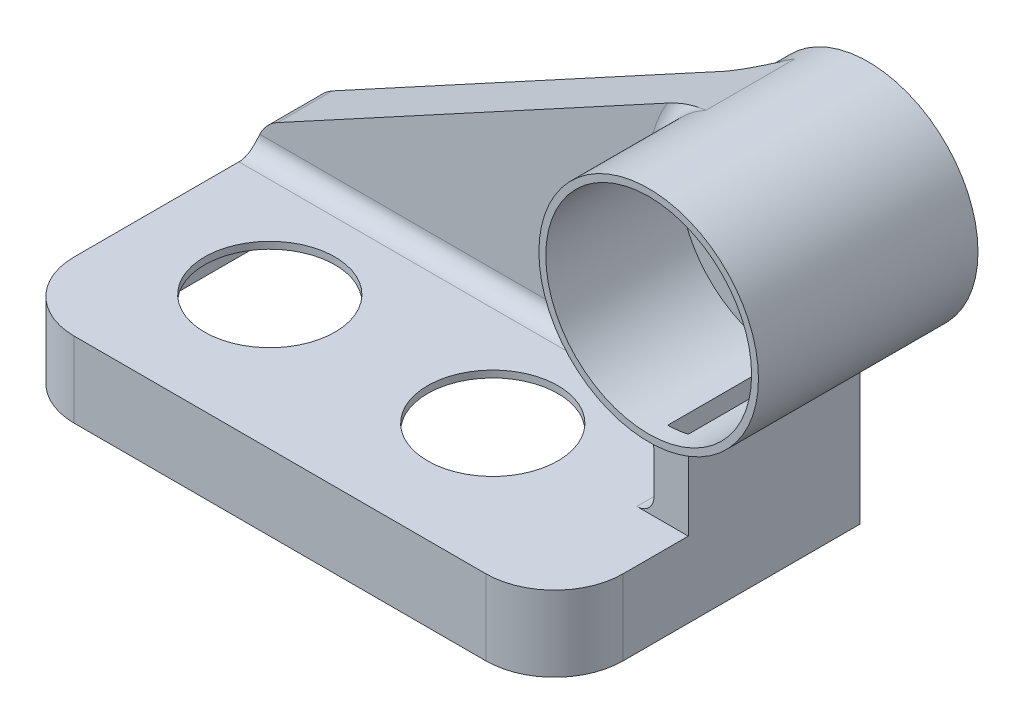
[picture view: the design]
ISO-10303-21;
HEADER;
FILE_DESCRIPTION(('STEP AP214'),'2;1');
FILE_NAME('part.step','',(''),(''),'','','');
FILE_SCHEMA(('AUTOMOTIVE_DESIGN { 1 0 10303 214 1 1 1 1 }'));
ENDSEC;
DATA;
#1=APPLICATION_CONTEXT('core data for automotive mechanical design processes');
#2=APPLICATION_PROTOCOL_DEFINITION('international standard','automotive_design',2000,#1);
#3=PRODUCT_CONTEXT('',#1,'mechanical');
#4=PRODUCT('Part','Part','',(#3));
#5=PRODUCT_RELATED_PRODUCT_CATEGORY('part','',(#4));
#6=PRODUCT_DEFINITION_FORMATION('','',#4);
#7=PRODUCT_DEFINITION_CONTEXT('part definition',#1,'design');
#8=PRODUCT_DEFINITION('design','',#6,#7);
#9=PRODUCT_DEFINITION_SHAPE('','',#8);
#10=(LENGTH_UNIT() NAMED_UNIT(*) SI_UNIT(.MILLI.,.METRE.));
#11=(NAMED_UNIT(*) PLANE_ANGLE_UNIT() SI_UNIT($,.RADIAN.));
#12=(NAMED_UNIT(*) SI_UNIT($,.STERADIAN.) SOLID_ANGLE_UNIT());
#13=UNCERTAINTY_MEASURE_WITH_UNIT(LENGTH_MEASURE(1.E-05),#10,'distance_accuracy_value','');
#14=(GEOMETRIC_REPRESENTATION_CONTEXT(3) GLOBAL_UNCERTAINTY_ASSIGNED_CONTEXT((#13)) GLOBAL_UNIT_ASSIGNED_CONTEXT((#10,
#11,#12)) REPRESENTATION_CONTEXT('',''));
#15=CARTESIAN_POINT('',(0.,0.,0.));
#16=DIRECTION('',(0.,0.,1.));
#17=DIRECTION('',(1.,0.,0.));
#18=AXIS2_PLACEMENT_3D('',#15,#16,#17);
#19=CARTESIAN_POINT('',(160.,22.,0.));
#20=DIRECTION('',(0.,1.,0.));
#21=DIRECTION('',(0.,0.,1.));
#22=AXIS2_PLACEMENT_3D('',#19,#20,#21);
#23=PLANE('',#22);
#24=CARTESIAN_POINT('',(38.,22.,-39.));
#25=DIRECTION('',(0.,1.,0.));
#26=DIRECTION('',(0.,0.,1.));
#27=AXIS2_PLACEMENT_3D('',#24,#25,#26);
#28=CIRCLE('',#27,19.);
#29=CARTESIAN_POINT('',(38.,22.,-20.));
#30=VERTEX_POINT('',#29);
#31=EDGE_CURVE('E988',#30,#30,#28,.T.);
#32=ORIENTED_EDGE('',*,*,#31,.F.);
#33=EDGE_LOOP('',(#32));
#34=FACE_BOUND('',#33,.T.);
#35=DIRECTION('',(0.,0.,1.));
#36=VECTOR('',#35,1.);
#37=CARTESIAN_POINT('',(145.,22.,0.));
#38=LINE('',#37,#36);
#39=CARTESIAN_POINT('',(145.,22.,-39.));
#40=VERTEX_POINT('',#39);
#41=CARTESIAN_POINT('',(145.,22.,-68.));
#42=VERTEX_POINT('',#41);
#43=EDGE_CURVE('E387',#40,#42,#38,.F.);
#44=ORIENTED_EDGE('',*,*,#43,.T.);
#45=DIRECTION('',(-1.,0.,0.));
#46=VECTOR('',#45,1.);
#47=CARTESIAN_POINT('',(160.,22.,-68.));
#48=LINE('',#47,#46);
#49=CARTESIAN_POINT('',(0.,22.,-68.));
#50=VERTEX_POINT('',#49);
#51=EDGE_CURVE('E484',#42,#50,#48,.T.);
#52=ORIENTED_EDGE('',*,*,#51,.T.);
#53=DIRECTION('',(0.,0.,-1.));
#54=VECTOR('',#53,1.);
#55=CARTESIAN_POINT('',(0.,22.,0.));
#56=LINE('',#55,#54);
#57=CARTESIAN_POINT('',(0.,22.,-20.));
#58=VERTEX_POINT('',#57);
#59=EDGE_CURVE('E403',#58,#50,#56,.T.);
#60=ORIENTED_EDGE('',*,*,#59,.F.);
#61=CARTESIAN_POINT('',(20.,22.,-20.));
#62=DIRECTION('',(0.,1.,0.));
#63=DIRECTION('',(0.,0.,1.));
#64=AXIS2_PLACEMENT_3D('',#61,#62,#63);
#65=CIRCLE('',#64,20.);
#66=CARTESIAN_POINT('',(20.,22.,0.));
#67=VERTEX_POINT('',#66);
#68=EDGE_CURVE('E437',#58,#67,#65,.T.);
#69=ORIENTED_EDGE('',*,*,#68,.T.);
#70=DIRECTION('',(1.,0.,0.));
#71=VECTOR('',#70,1.);
#72=CARTESIAN_POINT('',(0.,22.,0.));
#73=LINE('',#72,#71);
#74=CARTESIAN_POINT('',(140.,22.,0.));
#75=VERTEX_POINT('',#74);
#76=EDGE_CURVE('E372',#67,#75,#73,.T.);
#77=ORIENTED_EDGE('',*,*,#76,.T.);
#78=CARTESIAN_POINT('',(140.,22.,-20.));
#79=DIRECTION('',(0.,1.,0.));
#80=DIRECTION('',(0.,0.,1.));
#81=AXIS2_PLACEMENT_3D('',#78,#79,#80);
#82=CIRCLE('',#81,20.);
#83=CARTESIAN_POINT('',(160.,22.,-20.));
#84=VERTEX_POINT('',#83);
#85=EDGE_CURVE('E434',#75,#84,#82,.T.);
#86=ORIENTED_EDGE('',*,*,#85,.T.);
#87=DIRECTION('',(0.,0.,1.));
#88=VECTOR('',#87,1.);
#89=CARTESIAN_POINT('',(160.,22.,-89.));
#90=LINE('',#89,#88);
#91=CARTESIAN_POINT('',(160.,22.,-39.));
#92=VERTEX_POINT('',#91);
#93=EDGE_CURVE('E375',#92,#84,#90,.T.);
#94=ORIENTED_EDGE('',*,*,#93,.F.);
#95=DIRECTION('',(-1.,0.,0.));
#96=VECTOR('',#95,1.);
#97=CARTESIAN_POINT('',(160.,22.,-39.));
#98=LINE('',#97,#96);
#99=EDGE_CURVE('E337',#92,#40,#98,.T.);
#100=ORIENTED_EDGE('',*,*,#99,.T.);
#101=EDGE_LOOP('',(#44,#52,#60,#69,#77,#86,#94,#100));
#102=FACE_BOUND('',#101,.T.);
#103=CARTESIAN_POINT('',(103.,22.,-39.));
#104=DIRECTION('',(0.,1.,0.));
#105=DIRECTION('',(0.,0.,1.));
#106=AXIS2_PLACEMENT_3D('',#103,#104,#105);
#107=CIRCLE('',#106,19.);
#108=CARTESIAN_POINT('',(103.,22.,-20.));
#109=VERTEX_POINT('',#108);
#110=EDGE_CURVE('E499',#109,#109,#107,.T.);
#111=ORIENTED_EDGE('',*,*,#110,.F.);
#112=EDGE_LOOP('',(#111));
#113=FACE_BOUND('',#112,.T.);
#114=ADVANCED_FACE('F34',(#34,#102,#113),#23,.T.);
#115=CARTESIAN_POINT('',(160.,20.,0.));
#116=DIRECTION('',(0.,1.,0.));
#117=DIRECTION('',(0.,0.,1.));
#118=AXIS2_PLACEMENT_3D('',#115,#116,#117);
#119=PLANE('',#118);
#120=CARTESIAN_POINT('',(38.,20.,-39.));
#121=DIRECTION('',(0.,1.,0.));
#122=DIRECTION('',(0.,0.,1.));
#123=AXIS2_PLACEMENT_3D('',#120,#121,#122);
#124=CIRCLE('',#123,19.);
#125=CARTESIAN_POINT('',(38.,20.,-20.));
#126=VERTEX_POINT('',#125);
#127=EDGE_CURVE('E304',#126,#126,#124,.T.);
#128=ORIENTED_EDGE('',*,*,#127,.T.);
#129=EDGE_LOOP('',(#128));
#130=FACE_BOUND('',#129,.T.);
#131=DIRECTION('',(-1.,0.,0.));
#132=VECTOR('',#131,1.);
#133=CARTESIAN_POINT('',(160.,20.,-41.));
#134=LINE('',#133,#132);
#135=CARTESIAN_POINT('',(158.,20.,-41.));
#136=VERTEX_POINT('',#135);
#137=CARTESIAN_POINT('',(152.,20.,-41.));
#138=VERTEX_POINT('',#137);
#139=EDGE_CURVE('E227',#136,#138,#134,.T.);
#140=ORIENTED_EDGE('',*,*,#139,.F.);
#141=DIRECTION('',(0.,0.,1.));
#142=VECTOR('',#141,1.);
#143=CARTESIAN_POINT('',(158.,20.,-89.));
#144=LINE('',#143,#142);
#145=CARTESIAN_POINT('',(158.,20.,-20.));
#146=VERTEX_POINT('',#145);
#147=EDGE_CURVE('E269',#136,#146,#144,.T.);
#148=ORIENTED_EDGE('',*,*,#147,.T.);
#149=CARTESIAN_POINT('',(140.,20.,-20.));
#150=DIRECTION('',(0.,1.,0.));
#151=DIRECTION('',(0.,0.,1.));
#152=AXIS2_PLACEMENT_3D('',#149,#150,#151);
#153=CIRCLE('',#152,18.);
#154=CARTESIAN_POINT('',(140.,20.,-2.));
#155=VERTEX_POINT('',#154);
#156=EDGE_CURVE('E266',#155,#146,#153,.T.);
#157=ORIENTED_EDGE('',*,*,#156,.F.);
#158=DIRECTION('',(1.,0.,0.));
#159=VECTOR('',#158,1.);
#160=CARTESIAN_POINT('',(0.,20.,-2.));
#161=LINE('',#160,#159);
#162=CARTESIAN_POINT('',(20.,20.,-2.));
#163=VERTEX_POINT('',#162);
#164=EDGE_CURVE('E262',#163,#155,#161,.T.);
#165=ORIENTED_EDGE('',*,*,#164,.F.);
#166=CARTESIAN_POINT('',(20.,20.,-20.));
#167=DIRECTION('',(0.,1.,0.));
#168=DIRECTION('',(0.,0.,1.));
#169=AXIS2_PLACEMENT_3D('',#166,#167,#168);
#170=CIRCLE('',#169,18.);
#171=CARTESIAN_POINT('',(2.,20.,-20.));
#172=VERTEX_POINT('',#171);
#173=EDGE_CURVE('E263',#172,#163,#170,.T.);
#174=ORIENTED_EDGE('',*,*,#173,.F.);
#175=DIRECTION('',(0.,0.,-1.));
#176=VECTOR('',#175,1.);
#177=CARTESIAN_POINT('',(2.,20.,0.));
#178=LINE('',#177,#176);
#179=CARTESIAN_POINT('',(2.,20.,-75.));
#180=VERTEX_POINT('',#179);
#181=EDGE_CURVE('E259',#172,#180,#178,.T.);
#182=ORIENTED_EDGE('',*,*,#181,.T.);
#183=DIRECTION('',(-1.,0.,0.));
#184=VECTOR('',#183,1.);
#185=CARTESIAN_POINT('',(160.,20.,-75.));
#186=LINE('',#185,#184);
#187=CARTESIAN_POINT('',(152.,20.,-75.));
#188=VERTEX_POINT('',#187);
#189=EDGE_CURVE('E250',#188,#180,#186,.T.);
#190=ORIENTED_EDGE('',*,*,#189,.F.);
#191=DIRECTION('',(0.,0.,1.));
#192=VECTOR('',#191,1.);
#193=CARTESIAN_POINT('',(152.,20.,-73.));
#194=LINE('',#193,#192);
#195=EDGE_CURVE('E241',#188,#138,#194,.T.);
#196=ORIENTED_EDGE('',*,*,#195,.T.);
#197=EDGE_LOOP('',(#140,#148,#157,#165,#174,#182,#190,#196));
#198=FACE_BOUND('',#197,.T.);
#199=CARTESIAN_POINT('',(103.,20.,-39.));
#200=DIRECTION('',(0.,1.,0.));
#201=DIRECTION('',(0.,0.,1.));
#202=AXIS2_PLACEMENT_3D('',#199,#200,#201);
#203=CIRCLE('',#202,19.);
#204=CARTESIAN_POINT('',(103.,20.,-20.));
#205=VERTEX_POINT('',#204);
#206=EDGE_CURVE('E501',#205,#205,#203,.T.);
#207=ORIENTED_EDGE('',*,*,#206,.T.);
#208=EDGE_LOOP('',(#207));
#209=FACE_BOUND('',#208,.T.);
#210=ADVANCED_FACE('F247',(#130,#198,#209),#119,.F.);
#211=CARTESIAN_POINT('',(151.451853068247,75.,-73.));
#212=DIRECTION('',(0.,0.,-1.));
#213=DIRECTION('',(-1.,0.,0.));
#214=AXIS2_PLACEMENT_3D('',#211,#212,#213);
#215=PLANE('',#214);
#216=DIRECTION('',(0.,-1.,0.));
#217=VECTOR('',#216,1.);
#218=CARTESIAN_POINT('',(145.,38.5668613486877,-73.));
#219=LINE('',#218,#217);
#220=CARTESIAN_POINT('',(145.,27.,-73.));
#221=VERTEX_POINT('',#220);
#222=CARTESIAN_POINT('',(145.,38.5668613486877,-73.));
#223=VERTEX_POINT('',#222);
#224=EDGE_CURVE('E702',#221,#223,#219,.F.);
#225=ORIENTED_EDGE('',*,*,#224,.T.);
#226=CARTESIAN_POINT('',(151.451853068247,75.,-73.));
#227=DIRECTION('',(0.,0.,-1.));
#228=DIRECTION('',(-1.,0.,0.));
#229=AXIS2_PLACEMENT_3D('',#226,#227,#228);
#230=CIRCLE('',#229,37.);
#231=CARTESIAN_POINT('',(119.854697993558,94.2514880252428,-73.));
#232=VERTEX_POINT('',#231);
#233=EDGE_CURVE('E695',#223,#232,#230,.T.);
#234=ORIENTED_EDGE('',*,*,#233,.T.);
#235=DIRECTION('',(0.878698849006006,0.477376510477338,0.));
#236=VECTOR('',#235,1.);
#237=CARTESIAN_POINT('',(6.27148187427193,32.5443861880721,-73.));
#238=LINE('',#237,#236);
#239=CARTESIAN_POINT('',(6.27148187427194,32.5443861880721,-73.));
#240=VERTEX_POINT('',#239);
#241=EDGE_CURVE('E354',#240,#232,#238,.T.);
#242=ORIENTED_EDGE('',*,*,#241,.F.);
#243=CARTESIAN_POINT('',(12.,22.,-73.));
#244=DIRECTION('',(0.,0.,-1.));
#245=DIRECTION('',(-1.,0.,0.));
#246=AXIS2_PLACEMENT_3D('',#243,#244,#245);
#247=CIRCLE('',#246,12.);
#248=CARTESIAN_POINT('',(1.09128788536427,27.,-73.));
#249=VERTEX_POINT('',#248);
#250=EDGE_CURVE('E357',#249,#240,#247,.T.);
#251=ORIENTED_EDGE('',*,*,#250,.F.);
#252=DIRECTION('',(-1.,0.,0.));
#253=VECTOR('',#252,1.);
#254=CARTESIAN_POINT('',(151.451853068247,27.,-73.));
#255=LINE('',#254,#253);
#256=EDGE_CURVE('E397',#249,#221,#255,.F.);
#257=ORIENTED_EDGE('',*,*,#256,.T.);
#258=EDGE_LOOP('',(#225,#234,#242,#251,#257));
#259=FACE_BOUND('',#258,.T.);
#260=ADVANCED_FACE('F531',(#259),#215,.F.);
#261=CARTESIAN_POINT('',(160.,22.,-89.));
#262=DIRECTION('',(1.,0.,0.));
#263=DIRECTION('',(0.,0.,-1.));
#264=AXIS2_PLACEMENT_3D('',#261,#262,#263);
#265=PLANE('',#264);
#266=DIRECTION('',(0.,-1.,0.));
#267=VECTOR('',#266,1.);
#268=CARTESIAN_POINT('',(160.,107.001,-39.));
#269=LINE('',#268,#267);
#270=CARTESIAN_POINT('',(160.,44.1628603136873,-39.));
#271=VERTEX_POINT('',#270);
#272=EDGE_CURVE('E322',#271,#92,#269,.T.);
#273=ORIENTED_EDGE('',*,*,#272,.T.);
#274=ORIENTED_EDGE('',*,*,#93,.T.);
#275=DIRECTION('',(0.,-1.,0.));
#276=VECTOR('',#275,1.);
#277=CARTESIAN_POINT('',(160.,0.,-20.));
#278=LINE('',#277,#276);
#279=CARTESIAN_POINT('',(160.,0.,-20.));
#280=VERTEX_POINT('',#279);
#281=EDGE_CURVE('E385',#84,#280,#278,.T.);
#282=ORIENTED_EDGE('',*,*,#281,.T.);
#283=DIRECTION('',(0.,0.,1.));
#284=VECTOR('',#283,1.);
#285=CARTESIAN_POINT('',(160.,0.,-89.));
#286=LINE('',#285,#284);
#287=CARTESIAN_POINT('',(160.,0.,-89.));
#288=VERTEX_POINT('',#287);
#289=EDGE_CURVE('E369',#288,#280,#286,.T.);
#290=ORIENTED_EDGE('',*,*,#289,.F.);
#291=DIRECTION('',(0.,-1.,0.));
#292=VECTOR('',#291,1.);
#293=CARTESIAN_POINT('',(160.,22.,-89.));
#294=LINE('',#293,#292);
#295=CARTESIAN_POINT('',(160.,39.0009835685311,-89.));
#296=VERTEX_POINT('',#295);
#297=EDGE_CURVE('E418',#296,#288,#294,.T.);
#298=ORIENTED_EDGE('',*,*,#297,.F.);
#299=CARTESIAN_POINT('',(160.,39.0009835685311,-89.));
#300=CARTESIAN_POINT('',(160.,39.1493082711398,-88.9999869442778));
#301=CARTESIAN_POINT('',(160.,39.2976299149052,-89.0062472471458));
#302=CARTESIAN_POINT('',(160.,39.5932205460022,-89.031194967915));
#303=CARTESIAN_POINT('',(160.,39.7404895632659,-89.0498820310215));
#304=CARTESIAN_POINT('',(160.,40.0329217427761,-89.0995610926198));
#305=CARTESIAN_POINT('',(160.,40.1780851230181,-89.1305518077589));
#306=CARTESIAN_POINT('',(160.,40.4652910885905,-89.2046278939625));
#307=CARTESIAN_POINT('',(160.,40.6073337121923,-89.2477131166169));
#308=CARTESIAN_POINT('',(160.,40.8873409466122,-89.3457233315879));
#309=CARTESIAN_POINT('',(160.,41.0253038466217,-89.4006532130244));
#310=CARTESIAN_POINT('',(160.,41.2961367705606,-89.5220164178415));
#311=CARTESIAN_POINT('',(160.,41.4290048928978,-89.5884539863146));
#312=CARTESIAN_POINT('',(160.,41.6885226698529,-89.7323508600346));
#313=CARTESIAN_POINT('',(160.,41.8151762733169,-89.8098030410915));
#314=CARTESIAN_POINT('',(160.,42.0614332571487,-89.9752942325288));
#315=CARTESIAN_POINT('',(160.,42.1810342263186,-90.0633368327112));
#316=CARTESIAN_POINT('',(160.,42.411071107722,-90.2485064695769));
#317=CARTESIAN_POINT('',(160.,42.5215849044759,-90.3455367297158));
#318=CARTESIAN_POINT('',(160.,42.7338431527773,-90.5487553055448));
#319=CARTESIAN_POINT('',(160.,42.835587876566,-90.6549433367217));
#320=CARTESIAN_POINT('',(160.,43.0295005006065,-90.8758002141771));
#321=CARTESIAN_POINT('',(160.,43.1216650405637,-90.9904720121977));
#322=CARTESIAN_POINT('',(160.,43.2955459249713,-91.2274149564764));
#323=CARTESIAN_POINT('',(160.,43.3772664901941,-91.3496830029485));
#324=CARTESIAN_POINT('',(160.,43.5273765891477,-91.5973559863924));
#325=CARTESIAN_POINT('',(160.,43.596081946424,-91.7225695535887));
#326=CARTESIAN_POINT('',(160.,43.7223565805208,-91.9784296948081));
#327=CARTESIAN_POINT('',(160.,43.7799305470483,-92.1090739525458));
#328=CARTESIAN_POINT('',(160.,43.8834172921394,-92.37479813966));
#329=CARTESIAN_POINT('',(160.,43.9293383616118,-92.5098748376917));
#330=CARTESIAN_POINT('',(160.,44.0091328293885,-92.783488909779));
#331=CARTESIAN_POINT('',(160.,44.0430103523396,-92.9220250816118));
#332=CARTESIAN_POINT('',(160.,44.1013218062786,-93.2162653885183));
#333=CARTESIAN_POINT('',(160.,44.1243876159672,-93.372242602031));
#334=CARTESIAN_POINT('',(160.,44.155163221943,-93.6854814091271));
#335=CARTESIAN_POINT('',(160.,44.1628945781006,-93.8427408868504));
#336=CARTESIAN_POINT('',(160.,44.1628603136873,-94.));
#337=B_SPLINE_CURVE_WITH_KNOTS('',3,(#299,#300,#301,#302,#303,#304,#305,#306,#307,#308,#309,
#310,#311,#312,#313,#314,#315,#316,#317,#318,#319,#320,#321,#322,#323,#324,#325,#326,#327,#328,
#329,#330,#331,#332,#333,#334,#335,#336),.UNSPECIFIED.,.F.,.F.,(4,2,2,2,2,2,2,2,2,2,2,2,2,2,2,2,
2,2,4),(0.,0.444837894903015,0.889663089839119,1.33444189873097,1.77921525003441,
2.2241725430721,2.66929432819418,3.11412950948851,3.5591159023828,3.99977052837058,
4.44041146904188,4.88120644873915,5.32182272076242,5.74976598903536,6.17752856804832,
6.60498593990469,7.03229677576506,7.50455378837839,7.9761463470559),.UNSPECIFIED.);
#338=CARTESIAN_POINT('',(160.,44.1628603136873,-94.));
#339=VERTEX_POINT('',#338);
#340=EDGE_CURVE('E59',#296,#339,#337,.T.);
#341=ORIENTED_EDGE('',*,*,#340,.T.);
#342=DIRECTION('',(0.,0.,-1.));
#343=VECTOR('',#342,1.);
#344=CARTESIAN_POINT('',(160.,44.1628603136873,-73.));
#345=LINE('',#344,#343);
#346=EDGE_CURVE('E367',#271,#339,#345,.T.);
#347=ORIENTED_EDGE('',*,*,#346,.F.);
#348=EDGE_LOOP('',(#273,#274,#282,#290,#298,#341,#347));
#349=FACE_BOUND('',#348,.T.);
#350=ADVANCED_FACE('F443',(#349),#265,.T.);
#351=CARTESIAN_POINT('',(160.,22.,-89.));
#352=DIRECTION('',(0.,0.,1.));
#353=DIRECTION('',(1.,0.,0.));
#354=AXIS2_PLACEMENT_3D('',#351,#352,#353);
#355=PLANE('',#354);
#356=DIRECTION('',(0.878698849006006,0.477376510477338,0.));
#357=VECTOR('',#356,1.);
#358=CARTESIAN_POINT('',(6.27148187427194,32.5443861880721,-89.));
#359=LINE('',#358,#357);
#360=CARTESIAN_POINT('',(6.27148187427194,32.5443861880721,-89.));
#361=VERTEX_POINT('',#360);
#362=CARTESIAN_POINT('',(119.854697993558,94.2514880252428,-89.));
#363=VERTEX_POINT('',#362);
#364=EDGE_CURVE('E351',#361,#363,#359,.T.);
#365=ORIENTED_EDGE('',*,*,#364,.T.);
#366=CARTESIAN_POINT('',(151.451853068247,75.,-89.));
#367=DIRECTION('',(0.,0.,1.));
#368=DIRECTION('',(1.,0.,0.));
#369=AXIS2_PLACEMENT_3D('',#366,#367,#368);
#370=CIRCLE('',#369,37.);
#371=EDGE_CURVE('E492',#363,#296,#370,.T.);
#372=ORIENTED_EDGE('',*,*,#371,.T.);
#373=ORIENTED_EDGE('',*,*,#297,.T.);
#374=DIRECTION('',(-1.,0.,0.));
#375=VECTOR('',#374,1.);
#376=CARTESIAN_POINT('',(160.,0.,-89.));
#377=LINE('',#376,#375);
#378=CARTESIAN_POINT('',(0.,0.,-89.));
#379=VERTEX_POINT('',#378);
#380=EDGE_CURVE('E378',#288,#379,#377,.T.);
#381=ORIENTED_EDGE('',*,*,#380,.T.);
#382=DIRECTION('',(0.,-1.,0.));
#383=VECTOR('',#382,1.);
#384=CARTESIAN_POINT('',(0.,22.,-89.));
#385=LINE('',#384,#383);
#386=CARTESIAN_POINT('',(0.,22.,-89.));
#387=VERTEX_POINT('',#386);
#388=EDGE_CURVE('E411',#387,#379,#385,.T.);
#389=ORIENTED_EDGE('',*,*,#388,.F.);
#390=CARTESIAN_POINT('',(12.,22.,-89.));
#391=DIRECTION('',(0.,0.,-1.));
#392=DIRECTION('',(-1.,0.,0.));
#393=AXIS2_PLACEMENT_3D('',#390,#391,#392);
#394=CIRCLE('',#393,12.);
#395=EDGE_CURVE('E358',#387,#361,#394,.T.);
#396=ORIENTED_EDGE('',*,*,#395,.T.);
#397=EDGE_LOOP('',(#365,#372,#373,#381,#389,#396));
#398=FACE_BOUND('',#397,.T.);
#399=ADVANCED_FACE('F416',(#398),#355,.F.);
#400=CARTESIAN_POINT('',(0.,22.,0.));
#401=DIRECTION('',(-1.,0.,0.));
#402=DIRECTION('',(0.,0.,1.));
#403=AXIS2_PLACEMENT_3D('',#400,#401,#402);
#404=PLANE('',#403);
#405=DIRECTION('',(0.,0.,-1.));
#406=VECTOR('',#405,1.);
#407=CARTESIAN_POINT('',(0.,0.,0.));
#408=LINE('',#407,#406);
#409=CARTESIAN_POINT('',(0.,0.,-20.));
#410=VERTEX_POINT('',#409);
#411=EDGE_CURVE('E453',#410,#379,#408,.T.);
#412=ORIENTED_EDGE('',*,*,#411,.F.);
#413=DIRECTION('',(0.,-1.,0.));
#414=VECTOR('',#413,1.);
#415=CARTESIAN_POINT('',(0.,22.,-20.));
#416=LINE('',#415,#414);
#417=EDGE_CURVE('E432',#410,#58,#416,.F.);
#418=ORIENTED_EDGE('',*,*,#417,.T.);
#419=ORIENTED_EDGE('',*,*,#59,.T.);
#420=DIRECTION('',(0.,0.,-1.));
#421=VECTOR('',#420,1.);
#422=CARTESIAN_POINT('',(0.,22.,-73.));
#423=LINE('',#422,#421);
#424=EDGE_CURVE('E51',#50,#387,#423,.T.);
#425=ORIENTED_EDGE('',*,*,#424,.T.);
#426=ORIENTED_EDGE('',*,*,#388,.T.);
#427=EDGE_LOOP('',(#412,#418,#419,#425,#426));
#428=FACE_BOUND('',#427,.T.);
#429=ADVANCED_FACE('F410',(#428),#404,.T.);
#430=CARTESIAN_POINT('',(0.,22.,0.));
#431=DIRECTION('',(0.,0.,-1.));
#432=DIRECTION('',(-1.,0.,0.));
#433=AXIS2_PLACEMENT_3D('',#430,#431,#432);
#434=PLANE('',#433);
#435=ORIENTED_EDGE('',*,*,#76,.F.);
#436=DIRECTION('',(0.,-1.,0.));
#437=VECTOR('',#436,1.);
#438=CARTESIAN_POINT('',(20.,0.,0.));
#439=LINE('',#438,#437);
#440=CARTESIAN_POINT('',(20.,0.,0.));
#441=VERTEX_POINT('',#440);
#442=EDGE_CURVE('E425',#67,#441,#439,.T.);
#443=ORIENTED_EDGE('',*,*,#442,.T.);
#444=DIRECTION('',(1.,0.,0.));
#445=VECTOR('',#444,1.);
#446=CARTESIAN_POINT('',(0.,0.,0.));
#447=LINE('',#446,#445);
#448=CARTESIAN_POINT('',(140.,0.,0.));
#449=VERTEX_POINT('',#448);
#450=EDGE_CURVE('E451',#441,#449,#447,.T.);
#451=ORIENTED_EDGE('',*,*,#450,.T.);
#452=DIRECTION('',(0.,-1.,0.));
#453=VECTOR('',#452,1.);
#454=CARTESIAN_POINT('',(140.,22.,0.));
#455=LINE('',#454,#453);
#456=EDGE_CURVE('E420',#449,#75,#455,.F.);
#457=ORIENTED_EDGE('',*,*,#456,.T.);
#458=EDGE_LOOP('',(#435,#443,#451,#457));
#459=FACE_BOUND('',#458,.T.);
#460=ADVANCED_FACE('F467',(#459),#434,.F.);
#461=CARTESIAN_POINT('',(160.,0.,0.));
#462=DIRECTION('',(0.,1.,0.));
#463=DIRECTION('',(0.,0.,1.));
#464=AXIS2_PLACEMENT_3D('',#461,#462,#463);
#465=PLANE('',#464);
#466=CARTESIAN_POINT('',(20.,0.,-20.));
#467=DIRECTION('',(0.,1.,0.));
#468=DIRECTION('',(0.,0.,1.));
#469=AXIS2_PLACEMENT_3D('',#466,#467,#468);
#470=CIRCLE('',#469,18.);
#471=CARTESIAN_POINT('',(20.,0.,-2.));
#472=VERTEX_POINT('',#471);
#473=CARTESIAN_POINT('',(2.,0.,-20.));
#474=VERTEX_POINT('',#473);
#475=EDGE_CURVE('E285',#472,#474,#470,.F.);
#476=ORIENTED_EDGE('',*,*,#475,.F.);
#477=DIRECTION('',(1.,0.,0.));
#478=VECTOR('',#477,1.);
#479=CARTESIAN_POINT('',(0.,0.,-2.));
#480=LINE('',#479,#478);
#481=CARTESIAN_POINT('',(140.,0.,-2.));
#482=VERTEX_POINT('',#481);
#483=EDGE_CURVE('E325',#472,#482,#480,.T.);
#484=ORIENTED_EDGE('',*,*,#483,.T.);
#485=CARTESIAN_POINT('',(140.,0.,-20.));
#486=DIRECTION('',(0.,1.,0.));
#487=DIRECTION('',(0.,0.,1.));
#488=AXIS2_PLACEMENT_3D('',#485,#486,#487);
#489=CIRCLE('',#488,18.);
#490=CARTESIAN_POINT('',(158.,0.,-20.));
#491=VERTEX_POINT('',#490);
#492=EDGE_CURVE('E314',#491,#482,#489,.F.);
#493=ORIENTED_EDGE('',*,*,#492,.F.);
#494=DIRECTION('',(0.,0.,1.));
#495=VECTOR('',#494,1.);
#496=CARTESIAN_POINT('',(158.,0.,-89.));
#497=LINE('',#496,#495);
#498=CARTESIAN_POINT('',(158.,0.,-87.));
#499=VERTEX_POINT('',#498);
#500=EDGE_CURVE('E309',#499,#491,#497,.T.);
#501=ORIENTED_EDGE('',*,*,#500,.F.);
#502=DIRECTION('',(-1.,0.,0.));
#503=VECTOR('',#502,1.);
#504=CARTESIAN_POINT('',(160.,0.,-87.));
#505=LINE('',#504,#503);
#506=CARTESIAN_POINT('',(2.,0.,-87.));
#507=VERTEX_POINT('',#506);
#508=EDGE_CURVE('E273',#499,#507,#505,.T.);
#509=ORIENTED_EDGE('',*,*,#508,.T.);
#510=DIRECTION('',(0.,0.,-1.));
#511=VECTOR('',#510,1.);
#512=CARTESIAN_POINT('',(2.,0.,0.));
#513=LINE('',#512,#511);
#514=EDGE_CURVE('E323',#474,#507,#513,.T.);
#515=ORIENTED_EDGE('',*,*,#514,.F.);
#516=EDGE_LOOP('',(#476,#484,#493,#501,#509,#515));
#517=FACE_BOUND('',#516,.T.);
#518=ORIENTED_EDGE('',*,*,#450,.F.);
#519=CARTESIAN_POINT('',(20.,0.,-20.));
#520=DIRECTION('',(0.,1.,0.));
#521=DIRECTION('',(0.,0.,1.));
#522=AXIS2_PLACEMENT_3D('',#519,#520,#521);
#523=CIRCLE('',#522,20.);
#524=EDGE_CURVE('E430',#441,#410,#523,.F.);
#525=ORIENTED_EDGE('',*,*,#524,.T.);
#526=ORIENTED_EDGE('',*,*,#411,.T.);
#527=ORIENTED_EDGE('',*,*,#380,.F.);
#528=ORIENTED_EDGE('',*,*,#289,.T.);
#529=CARTESIAN_POINT('',(140.,0.,-20.));
#530=DIRECTION('',(0.,1.,0.));
#531=DIRECTION('',(0.,0.,1.));
#532=AXIS2_PLACEMENT_3D('',#529,#530,#531);
#533=CIRCLE('',#532,20.);
#534=EDGE_CURVE('E428',#280,#449,#533,.F.);
#535=ORIENTED_EDGE('',*,*,#534,.T.);
#536=EDGE_LOOP('',(#518,#525,#526,#527,#528,#535));
#537=FACE_BOUND('',#536,.T.);
#538=ADVANCED_FACE('F449',(#517,#537),#465,.F.);
#539=CARTESIAN_POINT('',(20.,22.,-20.));
#540=DIRECTION('',(0.,1.,0.));
#541=DIRECTION('',(0.,0.,1.));
#542=AXIS2_PLACEMENT_3D('',#539,#540,#541);
#543=CYLINDRICAL_SURFACE('',#542,20.);
#544=ORIENTED_EDGE('',*,*,#68,.F.);
#545=ORIENTED_EDGE('',*,*,#417,.F.);
#546=ORIENTED_EDGE('',*,*,#524,.F.);
#547=ORIENTED_EDGE('',*,*,#442,.F.);
#548=EDGE_LOOP('',(#544,#545,#546,#547));
#549=FACE_BOUND('',#548,.T.);
#550=ADVANCED_FACE('F460',(#549),#543,.T.);
#551=CARTESIAN_POINT('',(140.,22.,-20.));
#552=DIRECTION('',(0.,1.,0.));
#553=DIRECTION('',(0.,0.,1.));
#554=AXIS2_PLACEMENT_3D('',#551,#552,#553);
#555=CYLINDRICAL_SURFACE('',#554,20.);
#556=ORIENTED_EDGE('',*,*,#85,.F.);
#557=ORIENTED_EDGE('',*,*,#456,.F.);
#558=ORIENTED_EDGE('',*,*,#534,.F.);
#559=ORIENTED_EDGE('',*,*,#281,.F.);
#560=EDGE_LOOP('',(#556,#557,#558,#559));
#561=FACE_BOUND('',#560,.T.);
#562=ADVANCED_FACE('F469',(#561),#555,.T.);
#563=CARTESIAN_POINT('',(151.451853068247,75.,-73.));
#564=DIRECTION('',(0.,0.,-1.));
#565=DIRECTION('',(-1.,0.,0.));
#566=AXIS2_PLACEMENT_3D('',#563,#564,#565);
#567=CYLINDRICAL_SURFACE('',#566,32.);
#568=DIRECTION('',(0.,0.,-1.));
#569=VECTOR('',#568,1.);
#570=CARTESIAN_POINT('',(136.175804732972,103.118363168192,-73.));
#571=LINE('',#570,#569);
#572=CARTESIAN_POINT('',(136.175804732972,103.118363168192,-68.));
#573=VERTEX_POINT('',#572);
#574=CARTESIAN_POINT('',(136.175804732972,103.118363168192,-94.));
#575=VERTEX_POINT('',#574);
#576=EDGE_CURVE('E365',#573,#575,#571,.T.);
#577=ORIENTED_EDGE('',*,*,#576,.F.);
#578=CARTESIAN_POINT('',(151.451853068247,75.,-68.));
#579=DIRECTION('',(0.,0.,-1.));
#580=DIRECTION('',(-1.,0.,0.));
#581=AXIS2_PLACEMENT_3D('',#578,#579,#580);
#582=CIRCLE('',#581,32.);
#583=CARTESIAN_POINT('',(145.87187203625,43.4902584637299,-68.));
#584=VERTEX_POINT('',#583);
#585=EDGE_CURVE('E681',#573,#584,#582,.F.);
#586=ORIENTED_EDGE('',*,*,#585,.T.);
#587=DIRECTION('',(0.,0.,-1.));
#588=VECTOR('',#587,1.);
#589=CARTESIAN_POINT('',(145.87187203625,43.4902584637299,-73.));
#590=LINE('',#589,#588);
#591=CARTESIAN_POINT('',(145.87187203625,43.4902584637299,-39.));
#592=VERTEX_POINT('',#591);
#593=EDGE_CURVE('E390',#584,#592,#590,.F.);
#594=ORIENTED_EDGE('',*,*,#593,.T.);
#595=CARTESIAN_POINT('',(151.451853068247,75.,-39.));
#596=DIRECTION('',(0.,0.,1.));
#597=DIRECTION('',(1.,0.,0.));
#598=AXIS2_PLACEMENT_3D('',#595,#596,#597);
#599=CIRCLE('',#598,32.);
#600=EDGE_CURVE('E339',#592,#271,#599,.T.);
#601=ORIENTED_EDGE('',*,*,#600,.T.);
#602=ORIENTED_EDGE('',*,*,#346,.T.);
#603=CARTESIAN_POINT('',(151.451853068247,75.,-94.));
#604=DIRECTION('',(0.,0.,1.));
#605=DIRECTION('',(1.,0.,0.));
#606=AXIS2_PLACEMENT_3D('',#603,#604,#605);
#607=CIRCLE('',#606,32.);
#608=EDGE_CURVE('E683',#339,#575,#607,.F.);
#609=ORIENTED_EDGE('',*,*,#608,.T.);
#610=EDGE_LOOP('',(#577,#586,#594,#601,#602,#609));
#611=FACE_BOUND('',#610,.T.);
#612=CARTESIAN_POINT('',(151.451853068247,75.,-36.));
#613=DIRECTION('',(0.,0.,-1.));
#614=DIRECTION('',(-1.,0.,0.));
#615=AXIS2_PLACEMENT_3D('',#612,#613,#614);
#616=CIRCLE('',#615,32.);
#617=CARTESIAN_POINT('',(119.451853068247,75.,-36.));
#618=VERTEX_POINT('',#617);
#619=EDGE_CURVE('E348',#618,#618,#616,.T.);
#620=ORIENTED_EDGE('',*,*,#619,.T.);
#621=EDGE_LOOP('',(#620));
#622=FACE_BOUND('',#621,.T.);
#623=CARTESIAN_POINT('',(151.451853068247,75.,-100.));
#624=DIRECTION('',(0.,0.,-1.));
#625=DIRECTION('',(-1.,0.,0.));
#626=AXIS2_PLACEMENT_3D('',#623,#624,#625);
#627=CIRCLE('',#626,32.);
#628=CARTESIAN_POINT('',(119.451853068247,75.,-100.));
#629=VERTEX_POINT('',#628);
#630=EDGE_CURVE('E347',#629,#629,#627,.T.);
#631=ORIENTED_EDGE('',*,*,#630,.F.);
#632=EDGE_LOOP('',(#631));
#633=FACE_BOUND('',#632,.T.);
#634=ADVANCED_FACE('F536',(#611,#622,#633),#567,.T.);
#635=CARTESIAN_POINT('',(6.27148187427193,32.5443861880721,-73.));
#636=DIRECTION('',(-0.477376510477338,0.878698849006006,0.));
#637=DIRECTION('',(-0.878698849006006,-0.477376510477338,0.));
#638=AXIS2_PLACEMENT_3D('',#635,#636,#637);
#639=PLANE('',#638);
#640=ORIENTED_EDGE('',*,*,#364,.F.);
#641=DIRECTION('',(0.,0.,-1.));
#642=VECTOR('',#641,1.);
#643=CARTESIAN_POINT('',(6.27148187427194,32.5443861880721,-73.));
#644=LINE('',#643,#642);
#645=EDGE_CURVE('E363',#240,#361,#644,.T.);
#646=ORIENTED_EDGE('',*,*,#645,.F.);
#647=ORIENTED_EDGE('',*,*,#241,.T.);
#648=CARTESIAN_POINT('',(119.854697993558,94.2514880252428,-73.));
#649=CARTESIAN_POINT('',(120.016230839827,94.3392450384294,-72.9999960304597));
#650=CARTESIAN_POINT('',(120.177750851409,94.4269950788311,-72.9974455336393));
#651=CARTESIAN_POINT('',(120.500662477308,94.6024254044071,-72.987560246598));
#652=CARTESIAN_POINT('',(120.66205410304,94.6901056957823,-72.9802259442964));
#653=CARTESIAN_POINT('',(121.145730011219,94.9528754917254,-72.9515215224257));
#654=CARTESIAN_POINT('',(121.467717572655,95.1278037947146,-72.9234491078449));
#655=CARTESIAN_POINT('',(122.10942607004,95.4764289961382,-72.8516706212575));
#656=CARTESIAN_POINT('',(122.429150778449,95.6501279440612,-72.8080069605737));
#657=CARTESIAN_POINT('',(123.066947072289,95.9966277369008,-72.7068588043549));
#658=CARTESIAN_POINT('',(123.385018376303,96.1694284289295,-72.6493720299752));
#659=CARTESIAN_POINT('',(124.016319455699,96.512399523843,-72.5227801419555));
#660=CARTESIAN_POINT('',(124.329566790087,96.6825794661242,-72.4537875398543));
#661=CARTESIAN_POINT('',(124.954122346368,97.0218858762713,-72.3051956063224));
#662=CARTESIAN_POINT('',(125.265430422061,97.1910122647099,-72.2255954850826));
#663=CARTESIAN_POINT('',(126.196819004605,97.6970138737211,-71.972655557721));
#664=CARTESIAN_POINT('',(126.813961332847,98.032292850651,-71.7852601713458));
#665=CARTESIAN_POINT('',(128.168863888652,98.7683796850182,-71.3395166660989));
#666=CARTESIAN_POINT('',(128.904906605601,99.1682544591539,-71.0745234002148));
#667=CARTESIAN_POINT('',(130.3679952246,99.9631162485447,-70.5149675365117));
#668=CARTESIAN_POINT('',(131.095042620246,100.358104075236,-70.2204099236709));
#669=CARTESIAN_POINT('',(133.26990234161,101.539654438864,-69.3072041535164));
#670=CARTESIAN_POINT('',(134.70835259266,102.32113077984,-68.6601365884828));
#671=CARTESIAN_POINT('',(136.156314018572,103.107774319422,-68.0087679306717));
#672=CARTESIAN_POINT('',(136.166059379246,103.113068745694,-68.0043839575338));
#673=CARTESIAN_POINT('',(136.175804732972,103.118363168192,-68.));
#674=B_SPLINE_CURVE_WITH_KNOTS('',3,(#648,#649,#650,#651,#652,#653,#654,#655,#656,#657,#658,
#659,#660,#661,#662,#663,#664,#665,#666,#667,#668,#669,#670,#671,#672,#673),.UNSPECIFIED.,.F.,
.F.,(4,2,2,2,2,2,2,2,2,2,2,2,4),(0.,0.551453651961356,1.10285106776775,2.20495618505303,
3.30408591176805,4.40339696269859,5.49252870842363,6.58174159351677,8.76156260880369,
11.3964778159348,14.0309494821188,19.3109105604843,19.3466876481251),.UNSPECIFIED.);
#675=EDGE_CURVE('E491',#232,#573,#674,.T.);
#676=ORIENTED_EDGE('',*,*,#675,.T.);
#677=ORIENTED_EDGE('',*,*,#576,.T.);
#678=CARTESIAN_POINT('',(119.854697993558,94.2514880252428,-89.));
#679=CARTESIAN_POINT('',(120.016230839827,94.3392450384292,-89.0000039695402));
#680=CARTESIAN_POINT('',(120.177750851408,94.4269950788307,-89.0025544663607));
#681=CARTESIAN_POINT('',(120.500662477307,94.6024254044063,-89.012439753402));
#682=CARTESIAN_POINT('',(120.662054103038,94.6901056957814,-89.0197740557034));
#683=CARTESIAN_POINT('',(121.145730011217,94.9528754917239,-89.0484784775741));
#684=CARTESIAN_POINT('',(121.467717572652,95.1278037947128,-89.0765508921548));
#685=CARTESIAN_POINT('',(122.109426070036,95.4764289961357,-89.1483293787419));
#686=CARTESIAN_POINT('',(122.429150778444,95.6501279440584,-89.1919930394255));
#687=CARTESIAN_POINT('',(123.066947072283,95.9966277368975,-89.293141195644));
#688=CARTESIAN_POINT('',(123.385018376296,96.1694284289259,-89.3506279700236));
#689=CARTESIAN_POINT('',(124.016319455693,96.5123995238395,-89.4772198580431));
#690=CARTESIAN_POINT('',(124.329566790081,96.682579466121,-89.5462124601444));
#691=CARTESIAN_POINT('',(124.954122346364,97.0218858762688,-89.6948043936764));
#692=CARTESIAN_POINT('',(125.265430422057,97.1910122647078,-89.7744045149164));
#693=CARTESIAN_POINT('',(126.196819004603,97.69701387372,-90.0273444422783));
#694=CARTESIAN_POINT('',(126.813961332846,98.0322928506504,-90.2147398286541));
#695=CARTESIAN_POINT('',(128.168863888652,98.7683796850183,-90.6604833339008));
#696=CARTESIAN_POINT('',(128.904906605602,99.1682544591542,-90.9254765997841));
#697=CARTESIAN_POINT('',(130.3679952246,99.9631162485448,-91.4850324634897));
#698=CARTESIAN_POINT('',(131.095042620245,100.358104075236,-91.779590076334));
#699=CARTESIAN_POINT('',(133.269902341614,101.539654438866,-92.692795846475));
#700=CARTESIAN_POINT('',(134.708352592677,102.32113077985,-93.3398634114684));
#701=CARTESIAN_POINT('',(136.156314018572,103.107774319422,-93.9912320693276));
#702=CARTESIAN_POINT('',(136.166059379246,103.113068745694,-93.9956160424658));
#703=CARTESIAN_POINT('',(136.175804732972,103.118363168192,-94.));
#704=B_SPLINE_CURVE_WITH_KNOTS('',3,(#678,#679,#680,#681,#682,#683,#684,#685,#686,#687,#688,
#689,#690,#691,#692,#693,#694,#695,#696,#697,#698,#699,#700,#701,#702,#703),.UNSPECIFIED.,.F.,
.F.,(4,2,2,2,2,2,2,2,2,2,2,2,4),(0.,0.551453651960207,1.10285106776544,2.20495618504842,
3.30408591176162,4.40339696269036,5.4925287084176,6.58174159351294,8.76156260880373,
11.3964778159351,14.0309494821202,19.3109105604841,19.3466876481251),.UNSPECIFIED.);
#705=EDGE_CURVE('E44',#575,#363,#704,.F.);
#706=ORIENTED_EDGE('',*,*,#705,.T.);
#707=EDGE_LOOP('',(#640,#646,#647,#676,#677,#706));
#708=FACE_BOUND('',#707,.T.);
#709=ADVANCED_FACE('F530',(#708),#639,.T.);
#710=CARTESIAN_POINT('',(12.,22.,-73.));
#711=DIRECTION('',(0.,0.,-1.));
#712=DIRECTION('',(-1.,0.,0.));
#713=AXIS2_PLACEMENT_3D('',#710,#711,#712);
#714=CYLINDRICAL_SURFACE('',#713,12.);
#715=ORIENTED_EDGE('',*,*,#395,.F.);
#716=ORIENTED_EDGE('',*,*,#424,.F.);
#717=CARTESIAN_POINT('',(0.,22.,-68.));
#718=CARTESIAN_POINT('',(1.84980462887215E-05,21.999984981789,-68.1403882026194));
#719=CARTESIAN_POINT('',(5.8116985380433E-07,22.0059120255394,-68.2807742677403));
#720=CARTESIAN_POINT('',(2.56051773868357E-05,22.0295418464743,-68.5605464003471));
#721=CARTESIAN_POINT('',(6.85435859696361E-05,22.0472441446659,-68.6999325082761));
#722=CARTESIAN_POINT('',(0.000348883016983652,22.0943056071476,-68.9766588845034));
#723=CARTESIAN_POINT('',(0.000586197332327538,22.1236595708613,-69.114000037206));
#724=CARTESIAN_POINT('',(0.00151363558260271,22.1938110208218,-69.3857247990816));
#725=CARTESIAN_POINT('',(0.00220375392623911,22.2346083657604,-69.5201084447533));
#726=CARTESIAN_POINT('',(0.00437687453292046,22.3273763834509,-69.7850191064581));
#727=CARTESIAN_POINT('',(0.0058602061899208,22.3793516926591,-69.9155444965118));
#728=CARTESIAN_POINT('',(0.0100395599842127,22.4941103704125,-70.1717902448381));
#729=CARTESIAN_POINT('',(0.0127360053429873,22.5568975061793,-70.2975089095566));
#730=CARTESIAN_POINT('',(0.0198216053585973,22.6927845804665,-70.5431456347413));
#731=CARTESIAN_POINT('',(0.024210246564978,22.7658813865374,-70.6630654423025));
#732=CARTESIAN_POINT('',(0.0352055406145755,22.9218471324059,-70.8962639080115));
#733=CARTESIAN_POINT('',(0.0418121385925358,23.0047158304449,-71.0095427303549));
#734=CARTESIAN_POINT('',(0.057737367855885,23.1789660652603,-71.2278583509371));
#735=CARTESIAN_POINT('',(0.0670368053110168,23.270284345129,-71.3329470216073));
#736=CARTESIAN_POINT('',(0.0889007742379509,23.4611415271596,-71.5349369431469));
#737=CARTESIAN_POINT('',(0.101464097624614,23.5606773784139,-71.6318412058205));
#738=CARTESIAN_POINT('',(0.130369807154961,23.7671267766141,-71.8167695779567));
#739=CARTESIAN_POINT('',(0.146711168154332,23.8740383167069,-71.9047960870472));
#740=CARTESIAN_POINT('',(0.183642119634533,24.0943145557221,-72.0713704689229));
#741=CARTESIAN_POINT('',(0.204231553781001,24.207679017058,-72.1499186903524));
#742=CARTESIAN_POINT('',(0.249383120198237,24.4364301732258,-72.2948696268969));
#743=CARTESIAN_POINT('',(0.273811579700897,24.5516609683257,-72.3615601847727));
#744=CARTESIAN_POINT('',(0.327327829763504,24.7862527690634,-72.4851879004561));
#745=CARTESIAN_POINT('',(0.356417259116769,24.9056152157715,-72.5421216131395));
#746=CARTESIAN_POINT('',(0.419437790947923,25.1474081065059,-72.645988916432));
#747=CARTESIAN_POINT('',(0.453369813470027,25.2698391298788,-72.6929206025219));
#748=CARTESIAN_POINT('',(0.52613862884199,25.5166893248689,-72.7766939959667));
#749=CARTESIAN_POINT('',(0.564976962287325,25.6411091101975,-72.8135325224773));
#750=CARTESIAN_POINT('',(0.67440145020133,25.9721202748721,-72.897814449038));
#751=CARTESIAN_POINT('',(0.749227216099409,26.1796098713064,-72.9366120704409));
#752=CARTESIAN_POINT('',(0.870766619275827,26.4891551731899,-72.9749248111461));
#753=CARTESIAN_POINT('',(0.912796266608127,26.5919819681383,-72.9843821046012));
#754=CARTESIAN_POINT('',(0.999836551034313,26.7967458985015,-72.9969177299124));
#755=CARTESIAN_POINT('',(1.04484680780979,26.898683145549,-72.9999968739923));
#756=CARTESIAN_POINT('',(1.09128788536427,27.,-73.));
#757=B_SPLINE_CURVE_WITH_KNOTS('',3,(#717,#718,#719,#720,#721,#722,#723,#724,#725,#726,#727,
#728,#729,#730,#731,#732,#733,#734,#735,#736,#737,#738,#739,#740,#741,#742,#743,#744,#745,#746,
#747,#748,#749,#750,#751,#752,#753,#754,#755,#756),.UNSPECIFIED.,.F.,.F.,(4,2,2,2,2,2,2,2,2,2,2,
2,2,2,2,2,2,2,2,4),(0.,0.421036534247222,0.842055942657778,1.26288764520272,1.68371415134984,
2.10471554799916,2.52586393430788,2.94688463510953,3.36789492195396,3.78597527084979,
4.20390109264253,4.6217136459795,5.03951082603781,5.44509907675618,5.85083024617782,
6.25663860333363,6.66257470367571,7.33209329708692,7.66637139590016,8.00060692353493),.UNSPECIFIED.);
#758=EDGE_CURVE('E11',#50,#249,#757,.T.);
#759=ORIENTED_EDGE('',*,*,#758,.T.);
#760=ORIENTED_EDGE('',*,*,#250,.T.);
#761=ORIENTED_EDGE('',*,*,#645,.T.);
#762=EDGE_LOOP('',(#715,#716,#759,#760,#761));
#763=FACE_BOUND('',#762,.T.);
#764=ADVANCED_FACE('F525',(#763),#714,.T.);
#765=CARTESIAN_POINT('',(151.451853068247,75.,-36.));
#766=DIRECTION('',(0.,0.,-1.));
#767=DIRECTION('',(-1.,0.,0.));
#768=AXIS2_PLACEMENT_3D('',#765,#766,#767);
#769=PLANE('',#768);
#770=CARTESIAN_POINT('',(151.451853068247,75.,-36.));
#771=DIRECTION('',(0.,0.,-1.));
#772=DIRECTION('',(-1.,0.,0.));
#773=AXIS2_PLACEMENT_3D('',#770,#771,#772);
#774=CIRCLE('',#773,30.);
#775=CARTESIAN_POINT('',(121.451853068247,75.,-36.));
#776=VERTEX_POINT('',#775);
#777=EDGE_CURVE('E298',#776,#776,#774,.T.);
#778=ORIENTED_EDGE('',*,*,#777,.T.);
#779=EDGE_LOOP('',(#778));
#780=FACE_BOUND('',#779,.T.);
#781=ORIENTED_EDGE('',*,*,#619,.F.);
#782=EDGE_LOOP('',(#781));
#783=FACE_BOUND('',#782,.T.);
#784=ADVANCED_FACE('F529',(#780,#783),#769,.F.);
#785=CARTESIAN_POINT('',(151.451853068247,75.,-100.));
#786=DIRECTION('',(0.,0.,-1.));
#787=DIRECTION('',(-1.,0.,0.));
#788=AXIS2_PLACEMENT_3D('',#785,#786,#787);
#789=PLANE('',#788);
#790=CARTESIAN_POINT('',(151.451853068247,75.,-100.));
#791=DIRECTION('',(0.,0.,-1.));
#792=DIRECTION('',(-1.,0.,0.));
#793=AXIS2_PLACEMENT_3D('',#790,#791,#792);
#794=CIRCLE('',#793,30.);
#795=CARTESIAN_POINT('',(121.451853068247,75.,-100.));
#796=VERTEX_POINT('',#795);
#797=EDGE_CURVE('E316',#796,#796,#794,.T.);
#798=ORIENTED_EDGE('',*,*,#797,.F.);
#799=EDGE_LOOP('',(#798));
#800=FACE_BOUND('',#799,.T.);
#801=ORIENTED_EDGE('',*,*,#630,.T.);
#802=EDGE_LOOP('',(#801));
#803=FACE_BOUND('',#802,.T.);
#804=ADVANCED_FACE('F658',(#800,#803),#789,.T.);
#805=CARTESIAN_POINT('',(150.,107.001,-73.));
#806=DIRECTION('',(1.,0.,0.));
#807=DIRECTION('',(0.,0.,-1.));
#808=AXIS2_PLACEMENT_3D('',#805,#806,#807);
#809=PLANE('',#808);
#810=DIRECTION('',(0.,0.,-1.));
#811=VECTOR('',#810,1.);
#812=CARTESIAN_POINT('',(150.,38.5668613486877,-73.));
#813=LINE('',#812,#811);
#814=CARTESIAN_POINT('',(150.,38.5668613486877,-39.));
#815=VERTEX_POINT('',#814);
#816=CARTESIAN_POINT('',(150.,38.5668613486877,-68.));
#817=VERTEX_POINT('',#816);
#818=EDGE_CURVE('E381',#815,#817,#813,.T.);
#819=ORIENTED_EDGE('',*,*,#818,.T.);
#820=DIRECTION('',(0.,-1.,0.));
#821=VECTOR('',#820,1.);
#822=CARTESIAN_POINT('',(150.,27.,-68.));
#823=LINE('',#822,#821);
#824=CARTESIAN_POINT('',(150.,27.,-68.));
#825=VERTEX_POINT('',#824);
#826=EDGE_CURVE('E693',#817,#825,#823,.T.);
#827=ORIENTED_EDGE('',*,*,#826,.T.);
#828=DIRECTION('',(0.,0.,1.));
#829=VECTOR('',#828,1.);
#830=CARTESIAN_POINT('',(150.,27.,-73.));
#831=LINE('',#830,#829);
#832=CARTESIAN_POINT('',(150.,27.,-39.));
#833=VERTEX_POINT('',#832);
#834=EDGE_CURVE('E384',#825,#833,#831,.T.);
#835=ORIENTED_EDGE('',*,*,#834,.T.);
#836=DIRECTION('',(0.,-1.,0.));
#837=VECTOR('',#836,1.);
#838=CARTESIAN_POINT('',(150.,107.001,-39.));
#839=LINE('',#838,#837);
#840=EDGE_CURVE('E340',#815,#833,#839,.T.);
#841=ORIENTED_EDGE('',*,*,#840,.F.);
#842=EDGE_LOOP('',(#819,#827,#835,#841));
#843=FACE_BOUND('',#842,.T.);
#844=ADVANCED_FACE('F655',(#843),#809,.F.);
#845=CARTESIAN_POINT('',(160.,107.001,-39.));
#846=DIRECTION('',(0.,0.,1.));
#847=DIRECTION('',(1.,0.,0.));
#848=AXIS2_PLACEMENT_3D('',#845,#846,#847);
#849=PLANE('',#848);
#850=ORIENTED_EDGE('',*,*,#600,.F.);
#851=CARTESIAN_POINT('',(145.,38.5668613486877,-39.));
#852=DIRECTION('',(0.,0.,1.));
#853=DIRECTION('',(1.,0.,0.));
#854=AXIS2_PLACEMENT_3D('',#851,#852,#853);
#855=CIRCLE('',#854,5.);
#856=EDGE_CURVE('E395',#592,#815,#855,.F.);
#857=ORIENTED_EDGE('',*,*,#856,.T.);
#858=ORIENTED_EDGE('',*,*,#840,.T.);
#859=CARTESIAN_POINT('',(145.,27.,-39.));
#860=DIRECTION('',(0.,0.,1.));
#861=DIRECTION('',(1.,0.,0.));
#862=AXIS2_PLACEMENT_3D('',#859,#860,#861);
#863=CIRCLE('',#862,5.);
#864=EDGE_CURVE('E392',#833,#40,#863,.F.);
#865=ORIENTED_EDGE('',*,*,#864,.T.);
#866=ORIENTED_EDGE('',*,*,#99,.F.);
#867=ORIENTED_EDGE('',*,*,#272,.F.);
#868=EDGE_LOOP('',(#850,#857,#858,#865,#866,#867));
#869=FACE_BOUND('',#868,.T.);
#870=ADVANCED_FACE('F474',(#869),#849,.T.);
#871=CARTESIAN_POINT('',(151.451853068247,75.,-75.));
#872=DIRECTION('',(0.,0.,-1.));
#873=DIRECTION('',(-1.,0.,0.));
#874=AXIS2_PLACEMENT_3D('',#871,#872,#873);
#875=PLANE('',#874);
#876=DIRECTION('',(0.,-1.,0.));
#877=VECTOR('',#876,1.);
#878=CARTESIAN_POINT('',(152.,75.,-75.));
#879=LINE('',#878,#877);
#880=CARTESIAN_POINT('',(152.,45.0050081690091,-75.));
#881=VERTEX_POINT('',#880);
#882=EDGE_CURVE('E251',#881,#188,#879,.T.);
#883=ORIENTED_EDGE('',*,*,#882,.T.);
#884=ORIENTED_EDGE('',*,*,#189,.T.);
#885=DIRECTION('',(0.,-1.,0.));
#886=VECTOR('',#885,1.);
#887=CARTESIAN_POINT('',(2.,22.,-75.));
#888=LINE('',#887,#886);
#889=CARTESIAN_POINT('',(2.,22.,-75.));
#890=VERTEX_POINT('',#889);
#891=EDGE_CURVE('E277',#890,#180,#888,.T.);
#892=ORIENTED_EDGE('',*,*,#891,.F.);
#893=CARTESIAN_POINT('',(12.,22.,-75.));
#894=DIRECTION('',(0.,0.,-1.));
#895=DIRECTION('',(-1.,0.,0.));
#896=AXIS2_PLACEMENT_3D('',#893,#894,#895);
#897=CIRCLE('',#896,10.);
#898=CARTESIAN_POINT('',(7.22623489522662,30.7869884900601,-75.));
#899=VERTEX_POINT('',#898);
#900=EDGE_CURVE('E258',#890,#899,#897,.T.);
#901=ORIENTED_EDGE('',*,*,#900,.T.);
#902=DIRECTION('',(0.878698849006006,0.477376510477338,0.));
#903=VECTOR('',#902,1.);
#904=CARTESIAN_POINT('',(137.130557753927,101.36096547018,-75.));
#905=LINE('',#904,#903);
#906=CARTESIAN_POINT('',(137.130557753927,101.36096547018,-75.));
#907=VERTEX_POINT('',#906);
#908=EDGE_CURVE('E278',#899,#907,#905,.T.);
#909=ORIENTED_EDGE('',*,*,#908,.T.);
#910=CARTESIAN_POINT('',(151.451853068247,75.,-75.));
#911=DIRECTION('',(0.,0.,-1.));
#912=DIRECTION('',(-1.,0.,0.));
#913=AXIS2_PLACEMENT_3D('',#910,#911,#912);
#914=CIRCLE('',#913,30.);
#915=EDGE_CURVE('E275',#881,#907,#914,.T.);
#916=ORIENTED_EDGE('',*,*,#915,.F.);
#917=EDGE_LOOP('',(#883,#884,#892,#901,#909,#916));
#918=FACE_BOUND('',#917,.T.);
#919=ADVANCED_FACE('F611',(#918),#875,.T.);
#920=CARTESIAN_POINT('',(158.,22.,-89.));
#921=DIRECTION('',(1.,0.,0.));
#922=DIRECTION('',(0.,0.,-1.));
#923=AXIS2_PLACEMENT_3D('',#920,#921,#922);
#924=PLANE('',#923);
#925=DIRECTION('',(0.,-1.,0.));
#926=VECTOR('',#925,1.);
#927=CARTESIAN_POINT('',(158.,22.,-41.));
#928=LINE('',#927,#926);
#929=CARTESIAN_POINT('',(158.,45.7233579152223,-41.));
#930=VERTEX_POINT('',#929);
#931=EDGE_CURVE('E233',#930,#136,#928,.T.);
#932=ORIENTED_EDGE('',*,*,#931,.F.);
#933=DIRECTION('',(0.,0.,-1.));
#934=VECTOR('',#933,1.);
#935=CARTESIAN_POINT('',(158.,45.7233579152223,-41.));
#936=LINE('',#935,#934);
#937=CARTESIAN_POINT('',(158.,45.7233579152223,-87.));
#938=VERTEX_POINT('',#937);
#939=EDGE_CURVE('E307',#930,#938,#936,.T.);
#940=ORIENTED_EDGE('',*,*,#939,.T.);
#941=DIRECTION('',(0.,-1.,0.));
#942=VECTOR('',#941,1.);
#943=CARTESIAN_POINT('',(158.,22.,-87.));
#944=LINE('',#943,#942);
#945=EDGE_CURVE('E291',#938,#499,#944,.T.);
#946=ORIENTED_EDGE('',*,*,#945,.T.);
#947=ORIENTED_EDGE('',*,*,#500,.T.);
#948=DIRECTION('',(0.,1.,0.));
#949=VECTOR('',#948,1.);
#950=CARTESIAN_POINT('',(158.,22.,-20.));
#951=LINE('',#950,#949);
#952=EDGE_CURVE('E265',#146,#491,#951,.F.);
#953=ORIENTED_EDGE('',*,*,#952,.F.);
#954=ORIENTED_EDGE('',*,*,#147,.F.);
#955=EDGE_LOOP('',(#932,#940,#946,#947,#953,#954));
#956=FACE_BOUND('',#955,.T.);
#957=ADVANCED_FACE('F614',(#956),#924,.F.);
#958=CARTESIAN_POINT('',(160.,22.,-87.));
#959=DIRECTION('',(0.,0.,1.));
#960=DIRECTION('',(1.,0.,0.));
#961=AXIS2_PLACEMENT_3D('',#958,#959,#960);
#962=PLANE('',#961);
#963=DIRECTION('',(0.878698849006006,0.477376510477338,0.));
#964=VECTOR('',#963,1.);
#965=CARTESIAN_POINT('',(7.22623489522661,30.7869884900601,-87.));
#966=LINE('',#965,#964);
#967=CARTESIAN_POINT('',(7.22623489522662,30.7869884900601,-87.));
#968=VERTEX_POINT('',#967);
#969=CARTESIAN_POINT('',(137.130557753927,101.36096547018,-87.));
#970=VERTEX_POINT('',#969);
#971=EDGE_CURVE('E292',#968,#970,#966,.T.);
#972=ORIENTED_EDGE('',*,*,#971,.F.);
#973=CARTESIAN_POINT('',(12.,22.,-87.));
#974=DIRECTION('',(0.,0.,1.));
#975=DIRECTION('',(1.,0.,0.));
#976=AXIS2_PLACEMENT_3D('',#973,#974,#975);
#977=CIRCLE('',#976,10.);
#978=CARTESIAN_POINT('',(2.,22.,-87.));
#979=VERTEX_POINT('',#978);
#980=EDGE_CURVE('E281',#979,#968,#977,.F.);
#981=ORIENTED_EDGE('',*,*,#980,.F.);
#982=DIRECTION('',(0.,-1.,0.));
#983=VECTOR('',#982,1.);
#984=CARTESIAN_POINT('',(2.,22.,-87.));
#985=LINE('',#984,#983);
#986=EDGE_CURVE('E261',#979,#507,#985,.T.);
#987=ORIENTED_EDGE('',*,*,#986,.T.);
#988=ORIENTED_EDGE('',*,*,#508,.F.);
#989=ORIENTED_EDGE('',*,*,#945,.F.);
#990=CARTESIAN_POINT('',(151.451853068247,75.,-87.));
#991=DIRECTION('',(0.,0.,1.));
#992=DIRECTION('',(1.,0.,0.));
#993=AXIS2_PLACEMENT_3D('',#990,#991,#992);
#994=CIRCLE('',#993,30.);
#995=EDGE_CURVE('E295',#970,#938,#994,.T.);
#996=ORIENTED_EDGE('',*,*,#995,.F.);
#997=EDGE_LOOP('',(#972,#981,#987,#988,#989,#996));
#998=FACE_BOUND('',#997,.T.);
#999=ADVANCED_FACE('F618',(#998),#962,.T.);
#1000=CARTESIAN_POINT('',(2.,22.,0.));
#1001=DIRECTION('',(-1.,0.,0.));
#1002=DIRECTION('',(0.,0.,1.));
#1003=AXIS2_PLACEMENT_3D('',#1000,#1001,#1002);
#1004=PLANE('',#1003);
#1005=ORIENTED_EDGE('',*,*,#514,.T.);
#1006=ORIENTED_EDGE('',*,*,#986,.F.);
#1007=DIRECTION('',(0.,0.,1.));
#1008=VECTOR('',#1007,1.);
#1009=CARTESIAN_POINT('',(2.,22.,0.));
#1010=LINE('',#1009,#1008);
#1011=EDGE_CURVE('E257',#890,#979,#1010,.F.);
#1012=ORIENTED_EDGE('',*,*,#1011,.F.);
#1013=ORIENTED_EDGE('',*,*,#891,.T.);
#1014=ORIENTED_EDGE('',*,*,#181,.F.);
#1015=DIRECTION('',(0.,1.,0.));
#1016=VECTOR('',#1015,1.);
#1017=CARTESIAN_POINT('',(2.,22.,-20.));
#1018=LINE('',#1017,#1016);
#1019=EDGE_CURVE('E272',#474,#172,#1018,.T.);
#1020=ORIENTED_EDGE('',*,*,#1019,.F.);
#1021=EDGE_LOOP('',(#1005,#1006,#1012,#1013,#1014,#1020));
#1022=FACE_BOUND('',#1021,.T.);
#1023=ADVANCED_FACE('F622',(#1022),#1004,.F.);
#1024=CARTESIAN_POINT('',(0.,22.,-2.));
#1025=DIRECTION('',(0.,0.,-1.));
#1026=DIRECTION('',(-1.,0.,0.));
#1027=AXIS2_PLACEMENT_3D('',#1024,#1025,#1026);
#1028=PLANE('',#1027);
#1029=ORIENTED_EDGE('',*,*,#164,.T.);
#1030=DIRECTION('',(0.,1.,0.));
#1031=VECTOR('',#1030,1.);
#1032=CARTESIAN_POINT('',(140.,22.,-2.));
#1033=LINE('',#1032,#1031);
#1034=EDGE_CURVE('E300',#482,#155,#1033,.T.);
#1035=ORIENTED_EDGE('',*,*,#1034,.F.);
#1036=ORIENTED_EDGE('',*,*,#483,.F.);
#1037=DIRECTION('',(0.,1.,0.));
#1038=VECTOR('',#1037,1.);
#1039=CARTESIAN_POINT('',(20.,22.,-2.));
#1040=LINE('',#1039,#1038);
#1041=EDGE_CURVE('E312',#163,#472,#1040,.F.);
#1042=ORIENTED_EDGE('',*,*,#1041,.F.);
#1043=EDGE_LOOP('',(#1029,#1035,#1036,#1042));
#1044=FACE_BOUND('',#1043,.T.);
#1045=ADVANCED_FACE('F626',(#1044),#1028,.T.);
#1046=CARTESIAN_POINT('',(20.,22.,-20.));
#1047=DIRECTION('',(0.,1.,0.));
#1048=DIRECTION('',(0.,0.,1.));
#1049=AXIS2_PLACEMENT_3D('',#1046,#1047,#1048);
#1050=CYLINDRICAL_SURFACE('',#1049,18.);
#1051=ORIENTED_EDGE('',*,*,#173,.T.);
#1052=ORIENTED_EDGE('',*,*,#1041,.T.);
#1053=ORIENTED_EDGE('',*,*,#475,.T.);
#1054=ORIENTED_EDGE('',*,*,#1019,.T.);
#1055=EDGE_LOOP('',(#1051,#1052,#1053,#1054));
#1056=FACE_BOUND('',#1055,.T.);
#1057=ADVANCED_FACE('F630',(#1056),#1050,.F.);
#1058=CARTESIAN_POINT('',(140.,22.,-20.));
#1059=DIRECTION('',(0.,1.,0.));
#1060=DIRECTION('',(0.,0.,1.));
#1061=AXIS2_PLACEMENT_3D('',#1058,#1059,#1060);
#1062=CYLINDRICAL_SURFACE('',#1061,18.);
#1063=ORIENTED_EDGE('',*,*,#156,.T.);
#1064=ORIENTED_EDGE('',*,*,#952,.T.);
#1065=ORIENTED_EDGE('',*,*,#492,.T.);
#1066=ORIENTED_EDGE('',*,*,#1034,.T.);
#1067=EDGE_LOOP('',(#1063,#1064,#1065,#1066));
#1068=FACE_BOUND('',#1067,.T.);
#1069=ADVANCED_FACE('F634',(#1068),#1062,.F.);
#1070=CARTESIAN_POINT('',(151.451853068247,75.,-73.));
#1071=DIRECTION('',(0.,0.,-1.));
#1072=DIRECTION('',(-1.,0.,0.));
#1073=AXIS2_PLACEMENT_3D('',#1070,#1071,#1072);
#1074=CYLINDRICAL_SURFACE('',#1073,30.);
#1075=CARTESIAN_POINT('',(151.451853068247,75.,-41.));
#1076=DIRECTION('',(0.,0.,1.));
#1077=DIRECTION('',(1.,0.,0.));
#1078=AXIS2_PLACEMENT_3D('',#1075,#1076,#1077);
#1079=CIRCLE('',#1078,30.);
#1080=CARTESIAN_POINT('',(152.,45.0050081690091,-41.));
#1081=VERTEX_POINT('',#1080);
#1082=EDGE_CURVE('E236',#1081,#930,#1079,.T.);
#1083=ORIENTED_EDGE('',*,*,#1082,.F.);
#1084=DIRECTION('',(0.,0.,-1.));
#1085=VECTOR('',#1084,1.);
#1086=CARTESIAN_POINT('',(152.,45.0050081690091,-41.));
#1087=LINE('',#1086,#1085);
#1088=EDGE_CURVE('E244',#1081,#881,#1087,.T.);
#1089=ORIENTED_EDGE('',*,*,#1088,.T.);
#1090=ORIENTED_EDGE('',*,*,#915,.T.);
#1091=DIRECTION('',(0.,0.,1.));
#1092=VECTOR('',#1091,1.);
#1093=CARTESIAN_POINT('',(137.130557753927,101.36096547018,-73.));
#1094=LINE('',#1093,#1092);
#1095=EDGE_CURVE('E310',#907,#970,#1094,.F.);
#1096=ORIENTED_EDGE('',*,*,#1095,.T.);
#1097=ORIENTED_EDGE('',*,*,#995,.T.);
#1098=ORIENTED_EDGE('',*,*,#939,.F.);
#1099=EDGE_LOOP('',(#1083,#1089,#1090,#1096,#1097,#1098));
#1100=FACE_BOUND('',#1099,.T.);
#1101=ORIENTED_EDGE('',*,*,#777,.F.);
#1102=EDGE_LOOP('',(#1101));
#1103=FACE_BOUND('',#1102,.T.);
#1104=ORIENTED_EDGE('',*,*,#797,.T.);
#1105=EDGE_LOOP('',(#1104));
#1106=FACE_BOUND('',#1105,.T.);
#1107=ADVANCED_FACE('F638',(#1100,#1103,#1106),#1074,.F.);
#1108=CARTESIAN_POINT('',(7.22623489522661,30.7869884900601,-73.));
#1109=DIRECTION('',(-0.477376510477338,0.878698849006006,0.));
#1110=DIRECTION('',(-0.878698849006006,-0.477376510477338,0.));
#1111=AXIS2_PLACEMENT_3D('',#1108,#1109,#1110);
#1112=PLANE('',#1111);
#1113=ORIENTED_EDGE('',*,*,#971,.T.);
#1114=ORIENTED_EDGE('',*,*,#1095,.F.);
#1115=ORIENTED_EDGE('',*,*,#908,.F.);
#1116=DIRECTION('',(0.,0.,-1.));
#1117=VECTOR('',#1116,1.);
#1118=CARTESIAN_POINT('',(7.22623489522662,30.7869884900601,-73.));
#1119=LINE('',#1118,#1117);
#1120=EDGE_CURVE('E288',#899,#968,#1119,.T.);
#1121=ORIENTED_EDGE('',*,*,#1120,.T.);
#1122=EDGE_LOOP('',(#1113,#1114,#1115,#1121));
#1123=FACE_BOUND('',#1122,.T.);
#1124=ADVANCED_FACE('F642',(#1123),#1112,.F.);
#1125=CARTESIAN_POINT('',(12.,22.,-73.));
#1126=DIRECTION('',(0.,0.,-1.));
#1127=DIRECTION('',(-1.,0.,0.));
#1128=AXIS2_PLACEMENT_3D('',#1125,#1126,#1127);
#1129=CYLINDRICAL_SURFACE('',#1128,10.);
#1130=ORIENTED_EDGE('',*,*,#980,.T.);
#1131=ORIENTED_EDGE('',*,*,#1120,.F.);
#1132=ORIENTED_EDGE('',*,*,#900,.F.);
#1133=ORIENTED_EDGE('',*,*,#1011,.T.);
#1134=EDGE_LOOP('',(#1130,#1131,#1132,#1133));
#1135=FACE_BOUND('',#1134,.T.);
#1136=ADVANCED_FACE('F646',(#1135),#1129,.F.);
#1137=CARTESIAN_POINT('',(152.,107.001,-73.));
#1138=DIRECTION('',(1.,0.,0.));
#1139=DIRECTION('',(0.,0.,-1.));
#1140=AXIS2_PLACEMENT_3D('',#1137,#1138,#1139);
#1141=PLANE('',#1140);
#1142=DIRECTION('',(0.,-1.,0.));
#1143=VECTOR('',#1142,1.);
#1144=CARTESIAN_POINT('',(152.,107.001,-41.));
#1145=LINE('',#1144,#1143);
#1146=EDGE_CURVE('E231',#1081,#138,#1145,.T.);
#1147=ORIENTED_EDGE('',*,*,#1146,.T.);
#1148=ORIENTED_EDGE('',*,*,#195,.F.);
#1149=ORIENTED_EDGE('',*,*,#882,.F.);
#1150=ORIENTED_EDGE('',*,*,#1088,.F.);
#1151=EDGE_LOOP('',(#1147,#1148,#1149,#1150));
#1152=FACE_BOUND('',#1151,.T.);
#1153=ADVANCED_FACE('F240',(#1152),#1141,.T.);
#1154=CARTESIAN_POINT('',(160.,107.001,-41.));
#1155=DIRECTION('',(0.,0.,1.));
#1156=DIRECTION('',(1.,0.,0.));
#1157=AXIS2_PLACEMENT_3D('',#1154,#1155,#1156);
#1158=PLANE('',#1157);
#1159=ORIENTED_EDGE('',*,*,#1082,.T.);
#1160=ORIENTED_EDGE('',*,*,#931,.T.);
#1161=ORIENTED_EDGE('',*,*,#139,.T.);
#1162=ORIENTED_EDGE('',*,*,#1146,.F.);
#1163=EDGE_LOOP('',(#1159,#1160,#1161,#1162));
#1164=FACE_BOUND('',#1163,.T.);
#1165=ADVANCED_FACE('F230',(#1164),#1158,.F.);
#1166=CARTESIAN_POINT('',(38.,22.,-39.));
#1167=DIRECTION('',(0.,1.,0.));
#1168=DIRECTION('',(0.,0.,1.));
#1169=AXIS2_PLACEMENT_3D('',#1166,#1167,#1168);
#1170=CYLINDRICAL_SURFACE('',#1169,19.);
#1171=ORIENTED_EDGE('',*,*,#31,.T.);
#1172=EDGE_LOOP('',(#1171));
#1173=FACE_BOUND('',#1172,.T.);
#1174=ORIENTED_EDGE('',*,*,#127,.F.);
#1175=EDGE_LOOP('',(#1174));
#1176=FACE_BOUND('',#1175,.T.);
#1177=ADVANCED_FACE('F601',(#1173,#1176),#1170,.F.);
#1178=CARTESIAN_POINT('',(103.,22.,-39.));
#1179=DIRECTION('',(0.,1.,0.));
#1180=DIRECTION('',(0.,0.,1.));
#1181=AXIS2_PLACEMENT_3D('',#1178,#1179,#1180);
#1182=CYLINDRICAL_SURFACE('',#1181,19.);
#1183=ORIENTED_EDGE('',*,*,#110,.T.);
#1184=EDGE_LOOP('',(#1183));
#1185=FACE_BOUND('',#1184,.T.);
#1186=ORIENTED_EDGE('',*,*,#206,.F.);
#1187=EDGE_LOOP('',(#1186));
#1188=FACE_BOUND('',#1187,.T.);
#1189=ADVANCED_FACE('F595',(#1185,#1188),#1182,.F.);
#1190=CARTESIAN_POINT('',(145.,27.,-73.));
#1191=DIRECTION('',(0.,0.,1.));
#1192=DIRECTION('',(1.,0.,0.));
#1193=AXIS2_PLACEMENT_3D('',#1190,#1191,#1192);
#1194=CYLINDRICAL_SURFACE('',#1193,5.);
#1195=ORIENTED_EDGE('',*,*,#834,.F.);
#1196=CARTESIAN_POINT('',(145.,27.,-68.));
#1197=DIRECTION('',(0.,0.,1.));
#1198=DIRECTION('',(1.,0.,0.));
#1199=AXIS2_PLACEMENT_3D('',#1196,#1197,#1198);
#1200=CIRCLE('',#1199,5.);
#1201=EDGE_CURVE('E482',#825,#42,#1200,.F.);
#1202=ORIENTED_EDGE('',*,*,#1201,.T.);
#1203=ORIENTED_EDGE('',*,*,#43,.F.);
#1204=ORIENTED_EDGE('',*,*,#864,.F.);
#1205=EDGE_LOOP('',(#1195,#1202,#1203,#1204));
#1206=FACE_BOUND('',#1205,.T.);
#1207=ADVANCED_FACE('F480',(#1206),#1194,.F.);
#1208=CARTESIAN_POINT('',(145.,38.5668613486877,-73.));
#1209=DIRECTION('',(0.,0.,-1.));
#1210=DIRECTION('',(-1.,0.,0.));
#1211=AXIS2_PLACEMENT_3D('',#1208,#1209,#1210);
#1212=CYLINDRICAL_SURFACE('',#1211,5.);
#1213=ORIENTED_EDGE('',*,*,#593,.F.);
#1214=CARTESIAN_POINT('',(145.,38.5668613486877,-68.));
#1215=DIRECTION('',(0.,0.,-1.));
#1216=DIRECTION('',(-1.,0.,0.));
#1217=AXIS2_PLACEMENT_3D('',#1214,#1215,#1216);
#1218=CIRCLE('',#1217,5.);
#1219=EDGE_CURVE('E691',#584,#817,#1218,.T.);
#1220=ORIENTED_EDGE('',*,*,#1219,.T.);
#1221=ORIENTED_EDGE('',*,*,#818,.F.);
#1222=ORIENTED_EDGE('',*,*,#856,.F.);
#1223=EDGE_LOOP('',(#1213,#1220,#1221,#1222));
#1224=FACE_BOUND('',#1223,.T.);
#1225=ADVANCED_FACE('F560',(#1224),#1212,.F.);
#1226=CARTESIAN_POINT('',(160.,27.,-68.));
#1227=DIRECTION('',(-1.,0.,0.));
#1228=DIRECTION('',(0.,0.,1.));
#1229=AXIS2_PLACEMENT_3D('',#1226,#1227,#1228);
#1230=CYLINDRICAL_SURFACE('',#1229,5.);
#1231=ORIENTED_EDGE('',*,*,#758,.F.);
#1232=ORIENTED_EDGE('',*,*,#51,.F.);
#1233=CARTESIAN_POINT('',(145.,27.,-68.));
#1234=DIRECTION('',(-1.,0.,0.));
#1235=DIRECTION('',(0.,0.,1.));
#1236=AXIS2_PLACEMENT_3D('',#1233,#1234,#1235);
#1237=CIRCLE('',#1236,5.);
#1238=EDGE_CURVE('E39',#221,#42,#1237,.T.);
#1239=ORIENTED_EDGE('',*,*,#1238,.F.);
#1240=ORIENTED_EDGE('',*,*,#256,.F.);
#1241=EDGE_LOOP('',(#1231,#1232,#1239,#1240));
#1242=FACE_BOUND('',#1241,.T.);
#1243=ADVANCED_FACE('F488',(#1242),#1230,.F.);
#1244=CARTESIAN_POINT('',(145.,27.,-68.));
#1245=DIRECTION('',(0.,0.,1.));
#1246=DIRECTION('',(1.,0.,0.));
#1247=AXIS2_PLACEMENT_3D('',#1244,#1245,#1246);
#1248=SPHERICAL_SURFACE('',#1247,5.);
#1249=ORIENTED_EDGE('',*,*,#1238,.T.);
#1250=ORIENTED_EDGE('',*,*,#1201,.F.);
#1251=CARTESIAN_POINT('',(145.,27.,-68.));
#1252=DIRECTION('',(0.,-1.,0.));
#1253=DIRECTION('',(0.,0.,-1.));
#1254=AXIS2_PLACEMENT_3D('',#1251,#1252,#1253);
#1255=CIRCLE('',#1254,5.);
#1256=EDGE_CURVE('E497',#221,#825,#1255,.T.);
#1257=ORIENTED_EDGE('',*,*,#1256,.F.);
#1258=EDGE_LOOP('',(#1249,#1250,#1257));
#1259=FACE_BOUND('',#1258,.T.);
#1260=ADVANCED_FACE('F495',(#1259),#1248,.F.);
#1261=CARTESIAN_POINT('',(145.,107.001,-68.));
#1262=DIRECTION('',(0.,1.,0.));
#1263=DIRECTION('',(0.,0.,1.));
#1264=AXIS2_PLACEMENT_3D('',#1261,#1262,#1263);
#1265=CYLINDRICAL_SURFACE('',#1264,5.);
#1266=ORIENTED_EDGE('',*,*,#1256,.T.);
#1267=ORIENTED_EDGE('',*,*,#826,.F.);
#1268=CARTESIAN_POINT('',(145.,38.5668613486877,-68.));
#1269=DIRECTION('',(0.,-1.,0.));
#1270=DIRECTION('',(0.,0.,-1.));
#1271=AXIS2_PLACEMENT_3D('',#1268,#1269,#1270);
#1272=CIRCLE('',#1271,5.);
#1273=EDGE_CURVE('E503',#223,#817,#1272,.T.);
#1274=ORIENTED_EDGE('',*,*,#1273,.F.);
#1275=ORIENTED_EDGE('',*,*,#224,.F.);
#1276=EDGE_LOOP('',(#1266,#1267,#1274,#1275));
#1277=FACE_BOUND('',#1276,.T.);
#1278=ADVANCED_FACE('F564',(#1277),#1265,.F.);
#1279=CARTESIAN_POINT('',(145.,38.5668613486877,-68.));
#1280=DIRECTION('',(0.,0.,1.));
#1281=DIRECTION('',(1.,0.,0.));
#1282=AXIS2_PLACEMENT_3D('',#1279,#1280,#1281);
#1283=SPHERICAL_SURFACE('',#1282,5.);
#1284=ORIENTED_EDGE('',*,*,#1273,.T.);
#1285=ORIENTED_EDGE('',*,*,#1219,.F.);
#1286=CARTESIAN_POINT('',(145.,38.5668613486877,-68.));
#1287=DIRECTION('',(0.984679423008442,-0.174374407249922,0.));
#1288=DIRECTION('',(0.174374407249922,0.984679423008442,0.));
#1289=AXIS2_PLACEMENT_3D('',#1286,#1287,#1288);
#1290=CIRCLE('',#1289,5.);
#1291=EDGE_CURVE('E507',#223,#584,#1290,.T.);
#1292=ORIENTED_EDGE('',*,*,#1291,.F.);
#1293=EDGE_LOOP('',(#1284,#1285,#1292));
#1294=FACE_BOUND('',#1293,.T.);
#1295=ADVANCED_FACE('F558',(#1294),#1283,.F.);
#1296=CARTESIAN_POINT('',(151.451853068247,75.,-68.));
#1297=DIRECTION('',(0.,0.,-1.));
#1298=DIRECTION('',(-1.,0.,0.));
#1299=AXIS2_PLACEMENT_3D('',#1296,#1297,#1298);
#1300=TOROIDAL_SURFACE('',#1299,37.,5.);
#1301=ORIENTED_EDGE('',*,*,#1291,.T.);
#1302=ORIENTED_EDGE('',*,*,#585,.F.);
#1303=ORIENTED_EDGE('',*,*,#675,.F.);
#1304=ORIENTED_EDGE('',*,*,#233,.F.);
#1305=EDGE_LOOP('',(#1301,#1302,#1303,#1304));
#1306=FACE_BOUND('',#1305,.T.);
#1307=ADVANCED_FACE('F553',(#1306),#1300,.F.);
#1308=CARTESIAN_POINT('',(151.451853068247,75.,-94.));
#1309=DIRECTION('',(0.,0.,1.));
#1310=DIRECTION('',(1.,0.,0.));
#1311=AXIS2_PLACEMENT_3D('',#1308,#1309,#1310);
#1312=TOROIDAL_SURFACE('',#1311,37.,5.);
#1313=ORIENTED_EDGE('',*,*,#705,.F.);
#1314=ORIENTED_EDGE('',*,*,#608,.F.);
#1315=ORIENTED_EDGE('',*,*,#340,.F.);
#1316=ORIENTED_EDGE('',*,*,#371,.F.);
#1317=EDGE_LOOP('',(#1313,#1314,#1315,#1316));
#1318=FACE_BOUND('',#1317,.T.);
#1319=ADVANCED_FACE('F36',(#1318),#1312,.F.);
#1320=CLOSED_SHELL('',(#114,#210,#260,#350,#399,#429,#460,#538,#550,#562,#634,#709,#764,#784,
#804,#844,#870,#919,#957,#999,#1023,#1045,#1057,#1069,#1107,#1124,#1136,#1153,#1165,#1177,#1189,
#1207,#1225,#1243,#1260,#1278,#1295,#1307,#1319));
#1321=MANIFOLD_SOLID_BREP('B2',#1320);
#1322=ADVANCED_BREP_SHAPE_REPRESENTATION('',(#18,#1321),#14);
#1323=SHAPE_DEFINITION_REPRESENTATION(#9,#1322);
ENDSEC;
END-ISO-10303-21;
